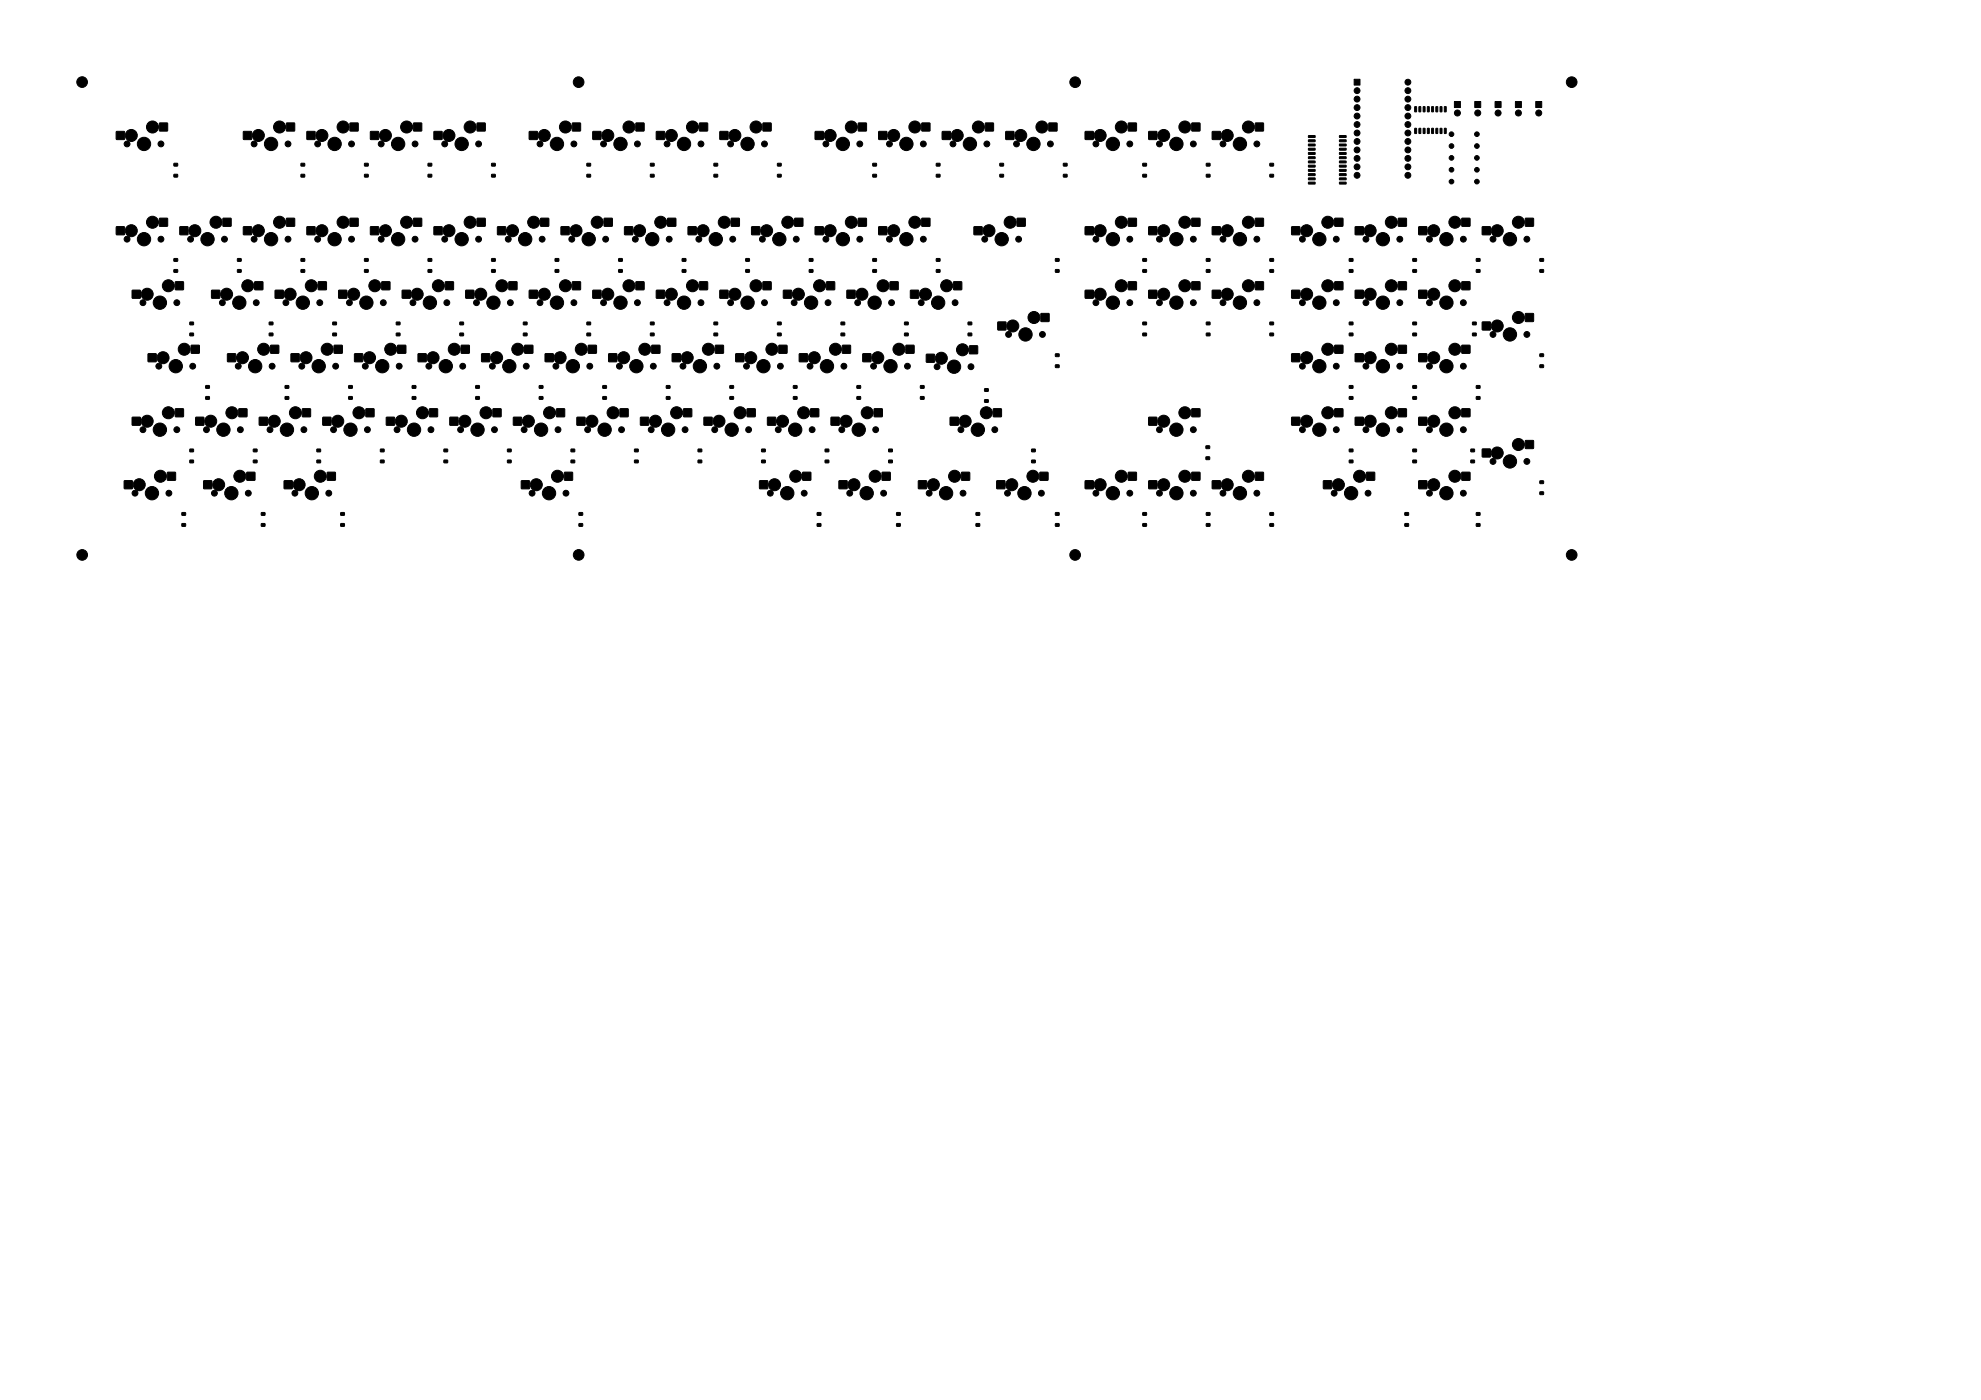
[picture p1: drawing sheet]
<svg xmlns="http://www.w3.org/2000/svg" width="594mm" height="420mm" viewBox="0 0 594 420" stroke-linecap="round" stroke-linejoin="round" font-family="sans-serif">
<g fill="#000" stroke="#000" stroke-width=".3">
<path d="M34.9 39.5h2.4v2.3h-2.4zM47.8 36.9h2.4v2.4h-2.4zM73 39.5h2.4v2.3h-2.4zM85.9 36.9h2.4v2.4h-2.4zM92 39.5h2.4v2.3h-2.4zM105 36.9h2.4v2.4h-2.4zM111.1 39.5h2.4v2.3h-2.4zM124 36.9h2.4v2.4h-2.4zM130.1 39.5h2.4v2.3h-2.4zM143.1 36.9h2.4v2.4h-2.4zM158.7 39.5h2.4v2.3h-2.4zM171.6 36.9h2.4v2.4h-2.4z"/>
<path d="M177.8 39.5h2.4v2.3h-2.4zM190.7 36.9h2.4v2.4h-2.4zM196.8 39.5h2.4v2.3h-2.4zM209.7 36.9h2.4v2.4h-2.4zM215.9 39.5h2.4v2.3h-2.4zM228.8 36.9h2.4v2.4h-2.4zM244.4 39.5h2.4v2.3h-2.4zM257.4 36.9h2.4v2.4h-2.4zM263.5 39.5h2.4v2.3h-2.4zM276.4 36.9h2.4v2.4h-2.4zM282.5 39.5h2.4v2.3h-2.4zM295.5 36.9h2.4v2.4h-2.4z"/>
<path d="M301.6 39.5h2.4v2.3h-2.4zM314.5 36.9h2.4v2.4h-2.4zM325.4 39.5h2.4v2.3h-2.4zM338.3 36.9h2.4v2.4h-2.4zM344.5 39.5h2.4v2.3h-2.4zM357.4 36.9h2.4v2.4h-2.4zM363.5 39.5h2.4v2.3h-2.4zM376.4 36.9h2.4v2.4h-2.4zM406 23.8h1.8v1.7h-1.8zM424.2 32l.6 .1-.1 1.5-.5-.1zM424.2 38.5l.6 .1-.1 1.5-.5-.1zM425.5 32l.5 .1v1.5l-.5-.1z"/>
<path d="M425.5 38.5l.5 .1v1.5l-.5-.1zM426.8 32l.5 .1-.1 1.5-.5-.1zM426.8 38.5l.5 .1-.1 1.5-.5-.1zM428 32l.6 .1-.1 1.5-.5-.1zM428 38.5l.6 .1-.1 1.5-.5-.1zM429.3 32l.5 .1v1.5l-.5-.1zM429.3 38.5l.5 .1v1.5l-.5-.1zM430.6 32l.5 .1-.1 1.5-.5-.1zM430.6 38.5l.5 .1-.1 1.5-.5-.1zM431.8 32l.6 .1-.1 1.5-.5-.1zM431.8 38.5l.6 .1-.1 1.5-.5-.1zM433.1 32l.6 .1-.1 1.5-.5-.1z"/>
<path d="M433.1 38.5l.6 .1-.1 1.5-.5-.1zM436.1 30.5h1.8v1.8h-1.8zM442.2 30.5h1.8v1.8h-1.8zM448.3 30.5h1.8v1.8h-1.8zM454.4 30.5h1.8v1.8h-1.8zM460.5 30.5h1.8v1.8h-1.8zM52.2 52.3h1v.8h-1zM52.2 49h1v.8h-1zM90.3 52.3h1v.8h-1zM90.3 49h1v.8h-1zM109.3 52.3h1.1v.8h-1.1zM109.3 49h1.1v.8h-1.1z"/>
<path d="M128.4 52.3h1v.8h-1zM128.4 49h1v.8h-1zM147.4 52.3h1.1v.8h-1.1zM147.4 49h1.1v.8h-1.1zM176 52.3h1.1v.8h-1.1zM176 49h1.1v.8h-1.1zM195 52.3h1.1v.8h-1.1zM195 49h1.1v.8h-1.1zM214.1 52.3h1.1v.8h-1.1zM214.1 49h1.1v.8h-1.1zM233.1 52.3h1.1v.8h-1.1zM233.1 49h1.1v.8h-1.1z"/>
<path d="M261.7 52.3h1.1v.8h-1.1zM261.7 49h1.1v.8h-1.1zM280.8 52.3h1v.8h-1zM280.8 49h1v.8h-1zM299.8 52.3h1.1v.8h-1.1zM299.8 49h1.1v.8h-1.1zM318.9 52.3h1v.8h-1zM318.9 49h1v.8h-1zM342.7 52.3h1.1v.8h-1.1zM342.7 49h1.1v.8h-1.1zM361.7 52.3h1.1v.8h-1.1zM361.7 49h1.1v.8h-1.1z"/>
<path d="M380.8 52.3h1.1v.8h-1.1zM380.8 49h1.1v.8h-1.1zM392.4 54.7l1.9-.1 .1 .5-2 .1zM392.4 53.4h1.9l.1 .5h-2zM392.4 52.1h1.9l.1 .5-2 .1zM392.4 50.9l1.9-.1 .1 .5-2 .1zM392.4 49.6h1.9l.1 .5h-2zM392.4 48.3h1.9l.1 .5-2 .1zM392.4 47.1l1.9-.1 .1 .5-2 .1zM392.4 45.8l1.9-.1 .1 .5-2 .1zM392.4 44.5h1.9l.1 .5-2 .1zM392.4 43.2h1.9l.1 .5-2 .1z"/>
<path d="M392.4 42l1.9-.1 .1 .5-2 .1zM392.4 40.7h1.9l.1 .5h-2zM401.7 40.7h1.9v.5h-1.9zM401.7 42l1.9-.1v.5l-1.9 .1zM401.7 43.2h1.9v.5l-1.9 .1zM401.7 44.5h1.9v.5l-1.9 .1zM401.7 45.8l1.9-.1v.5l-1.9 .1zM401.7 47.1l1.9-.1v.5l-1.9 .1zM401.7 48.3h1.9v.5l-1.9 .1zM401.7 49.6h1.9v.5h-1.9zM401.7 50.9l1.9-.1v.5l-1.9 .1zM401.7 52.1h1.9v.5l-1.9 .1z"/>
<path d="M401.7 53.4h1.9v.5h-1.9zM401.7 54.7l1.9-.1v.5l-1.9 .1zM34.9 68h2.4v2.4h-2.4zM47.8 65.5h2.4v2.4h-2.4zM52.2 77.6h1v.8h-1zM53.9 68h2.4v2.4h-2.4zM66.9 65.5h2.4v2.4h-2.4zM71.2 77.6h1.1v.8h-1.1zM73 68h2.4v2.4h-2.4zM85.9 65.5h2.4v2.4h-2.4zM90.3 77.6h1v.8h-1zM92 68h2.4v2.4h-2.4z"/>
<path d="M105 65.5h2.4v2.4h-2.4zM109.3 77.6h1.1v.8h-1.1zM111.1 68h2.4v2.4h-2.4zM124 65.5h2.4v2.4h-2.4zM128.4 77.6h1v.8h-1zM130.1 68h2.4v2.4h-2.4zM143.1 65.5h2.4v2.4h-2.4zM147.4 77.6h1.1v.8h-1.1zM149.2 68h2.4v2.4h-2.4zM162.1 65.5h2.4v2.4h-2.4zM166.5 77.6h1v.8h-1zM168.2 68h2.4v2.4h-2.4z"/>
<path d="M181.2 65.5h2.4v2.4h-2.4zM185.5 77.6h1.1v.8h-1.1zM187.3 68h2.4v2.4h-2.4zM200.2 65.5h2.4v2.4h-2.4zM204.6 77.6h1v.8h-1zM206.3 68h2.4v2.4h-2.4zM219.3 65.5h2.4v2.4h-2.4zM223.6 77.6h1.1v.8h-1.1zM225.4 68h2.4v2.4h-2.4zM238.3 65.5h2.4v2.4h-2.4zM242.7 77.6h1v.8h-1zM244.4 68h2.4v2.4h-2.4z"/>
<path d="M257.4 65.5h2.4v2.4h-2.4zM261.7 77.6h1.1v.8h-1.1zM263.5 68h2.4v2.4h-2.4zM276.4 65.5h2.4v2.4h-2.4zM280.8 77.6h1v.8h-1zM292.1 68h2.4v2.4h-2.4zM305 65.5h2.4v2.4h-2.4zM316.5 77.6h1.1v.8h-1.1zM325.4 68h2.4v2.4h-2.4zM338.3 65.5h2.4v2.4h-2.4zM342.7 77.6h1.1v.8h-1.1zM344.5 68h2.4v2.4h-2.4z"/>
<path d="M357.4 65.5h2.4v2.4h-2.4zM361.7 77.6h1.1v.8h-1.1zM363.5 68h2.4v2.4h-2.4zM376.4 65.5h2.4v2.4h-2.4zM380.8 77.6h1.1v.8h-1.1zM387.3 68h2.4v2.4h-2.4zM400.2 65.5h2.4v2.4h-2.4zM404.6 77.6h1.1v.8h-1.1zM406.4 68h2.4v2.4h-2.4zM419.3 65.5h2.4v2.4h-2.4zM423.6 77.6h1.1v.8h-1.1zM425.4 68h2.4v2.4h-2.4z"/>
<path d="M438.3 65.5h2.4v2.4h-2.4zM442.7 77.6h1.1v.8h-1.1zM444.5 68h2.4v2.4h-2.4zM457.4 65.5h2.4v2.4h-2.4zM461.7 77.6h1.1v.8h-1.1zM39.7 87.1h2.4v2.3h-2.4zM52.2 80.9h1v.8h-1zM52.6 84.5h2.4v2.4h-2.4zM56.9 96.6h1.1v.8h-1.1zM63.5 87.1h2.4v2.3h-2.4zM71.2 80.9h1.1v.8h-1.1zM76.4 84.5h2.4v2.4h-2.4z"/>
<path d="M80.7 96.6h1.1v.8h-1.1zM82.5 87.1h2.4v2.3h-2.4zM90.3 80.9h1v.8h-1zM95.4 84.5h2.4v2.4h-2.4zM99.8 96.6h1.1v.8h-1.1zM101.6 87.1h2.4v2.3h-2.4zM109.3 80.9h1.1v.8h-1.1zM114.5 84.5h2.4v2.4h-2.4zM118.8 96.6h1.1v.8h-1.1zM120.6 87.1h2.4v2.3h-2.4zM128.4 80.9h1v.8h-1zM133.5 84.5h2.4v2.4h-2.4z"/>
<path d="M137.9 96.6h1.1v.8h-1.1zM139.7 87.1h2.4v2.3h-2.4zM147.4 80.9h1.1v.8h-1.1zM152.6 84.5h2.4v2.4h-2.4zM156.9 96.6h1.1v.8h-1.1zM158.7 87.1h2.4v2.3h-2.4zM166.5 80.9h1v.8h-1zM171.6 84.5h2.4v2.4h-2.4zM176 96.6h1.1v.8h-1.1zM177.8 87.1h2.4v2.3h-2.4zM185.5 80.9h1.1v.8h-1.1zM190.7 84.5h2.4v2.4h-2.4z"/>
<path d="M195 96.6h1.1v.8h-1.1zM196.8 87.1h2.4v2.3h-2.4zM204.6 80.9h1v.8h-1zM209.7 84.5h2.4v2.4h-2.4zM214.1 96.6h1.1v.8h-1.1zM215.9 87.1h2.4v2.3h-2.4zM223.6 80.9h1.1v.8h-1.1zM228.8 84.5h2.4v2.4h-2.4zM233.1 96.6h1.1v.8h-1.1zM234.9 87.1h2.4v2.3h-2.4zM242.7 80.9h1v.8h-1zM247.8 84.5h2.4v2.4h-2.4z"/>
<path d="M252.2 96.6h1.1v.8h-1.1zM254 87.1h2.4v2.3h-2.4zM261.7 80.9h1.1v.8h-1.1zM266.9 84.5h2.4v2.4h-2.4zM271.2 96.6h1.1v.8h-1.1zM273 87.1h2.4v2.3h-2.4zM280.8 80.9h1v.8h-1zM285.9 84.5h2.4v2.4h-2.4zM290.3 96.6h1.1v.8h-1.1zM299.2 96.6h2.4v2.4h-2.4zM312.1 94.1h2.4v2.3h-2.4zM316.5 80.9h1.1v.8h-1.1z"/>
<path d="M325.4 87.1h2.4v2.3h-2.4zM338.3 84.5h2.4v2.4h-2.4zM342.7 80.9h1.1v.8h-1.1zM342.7 96.6h1.1v.8h-1.1zM344.5 87.1h2.4v2.3h-2.4zM357.4 84.5h2.4v2.4h-2.4zM361.7 80.9h1.1v.8h-1.1zM361.7 96.6h1.1v.8h-1.1zM363.5 87.1h2.4v2.3h-2.4zM376.4 84.5h2.4v2.4h-2.4zM380.8 80.9h1.1v.8h-1.1zM380.8 96.6h1.1v.8h-1.1z"/>
<path d="M387.3 87.1h2.4v2.3h-2.4zM400.2 84.5h2.4v2.4h-2.4zM404.6 96.6h1.1v.8h-1.1zM404.6 80.9h1.1v.8h-1.1zM406.4 87.1h2.4v2.3h-2.4zM419.3 84.5h2.4v2.4h-2.4zM423.6 80.9h1.1v.8h-1.1zM423.6 96.6h1.1v.8h-1.1zM425.4 87.1h2.4v2.3h-2.4zM438.3 84.5h2.4v2.4h-2.4zM441.6 96.6h1v.8h-1zM442.7 80.9h1.1v.8h-1.1z"/>
<path d="M444.5 96.6h2.4v2.4h-2.4zM457.4 94.1h2.4v2.3h-2.4zM461.7 80.9h1.1v.8h-1.1zM44.4 106.1h2.4v2.4h-2.4zM56.9 99.9h1.1v.8h-1.1zM57.3 103.6h2.4v2.4h-2.4zM61.7 119h1.1v.8h-1.1zM61.7 115.7h1.1v.8h-1.1zM68.2 106.1h2.4v2.4h-2.4zM80.7 99.9h1.1v.8h-1.1zM81.2 103.6h2.4v2.4h-2.4zM85.5 119h1.1v.8h-1.1z"/>
<path d="M85.5 115.7h1.1v.8h-1.1zM87.3 106.1h2.4v2.4h-2.4zM99.8 99.9h1.1v.8h-1.1zM100.2 103.6h2.4v2.4h-2.4zM104.6 119h1v.8h-1zM104.6 115.7h1v.8h-1zM106.3 106.1h2.4v2.4h-2.4zM118.8 99.9h1.1v.8h-1.1zM119.3 103.6h2.4v2.4h-2.4zM123.6 119h1.1v.8h-1.1zM123.6 115.7h1.1v.8h-1.1zM125.4 106.1h2.4v2.4h-2.4z"/>
<path d="M137.9 99.9h1.1v.8h-1.1zM138.3 103.6h2.4v2.4h-2.4zM142.7 119h1v.8h-1zM142.7 115.7h1v.8h-1zM144.4 106.1h2.4v2.4h-2.4zM156.9 99.9h1.1v.8h-1.1zM157.4 103.6h2.4v2.4h-2.4zM161.7 119h1.1v.8h-1.1zM161.7 115.7h1.1v.8h-1.1zM163.5 106.1h2.4v2.4h-2.4zM176 99.9h1.1v.8h-1.1zM176.4 103.6h2.4v2.4h-2.4z"/>
<path d="M180.8 119h1v.8h-1zM180.8 115.7h1v.8h-1zM182.5 106.1h2.4v2.4h-2.4zM195 99.9h1.1v.8h-1.1zM195.5 103.6h2.4v2.4h-2.4zM199.8 119h1.1v.8h-1.1zM199.8 115.7h1.1v.8h-1.1zM201.6 106.1h2.4v2.4h-2.4zM214.1 99.9h1.1v.8h-1.1zM214.5 103.6h2.4v2.4h-2.4zM218.9 119h1v.8h-1zM218.9 115.7h1v.8h-1z"/>
<path d="M220.6 106.1h2.4v2.4h-2.4zM233.1 99.9h1.1v.8h-1.1zM233.6 103.6h2.4v2.4h-2.4zM237.9 119h1.1v.8h-1.1zM237.9 115.7h1.1v.8h-1.1zM239.7 106.1h2.4v2.4h-2.4zM252.2 99.9h1.1v.8h-1.1zM252.6 103.6h2.4v2.4h-2.4zM257 119h1v.8h-1zM257 115.7h1v.8h-1zM258.7 106.1h2.4v2.4h-2.4zM271.2 99.9h1.1v.8h-1.1z"/>
<path d="M271.7 103.6h2.4v2.4h-2.4zM276 119h1.1v.8h-1.1zM276 115.7h1.1v.8h-1.1zM277.8 106.3h2.4v2.4h-2.4zM290.3 99.9h1.1v.8h-1.1zM290.7 103.8h2.4v2.3h-2.4zM295.2 116.6h1.1v.8h-1.1zM316.5 109.5h1.1v.7h-1.1zM316.5 106.2h1.1v.7h-1.1zM342.7 99.9h1.1v.8h-1.1zM361.7 99.9h1.1v.8h-1.1zM380.8 99.9h1.1v.8h-1.1z"/>
<path d="M387.3 106.1h2.4v2.4h-2.4zM400.2 103.6h2.4v2.4h-2.4zM404.6 99.9h1.1v.8h-1.1zM404.6 119h1.1v.8h-1.1zM404.6 115.7h1.1v.8h-1.1zM406.4 106.1h2.4v2.4h-2.4zM419.3 103.6h2.4v2.4h-2.4zM423.6 119h1.1v.8h-1.1zM423.6 115.7h1.1v.8h-1.1zM423.6 99.9h1.1v.8h-1.1zM425.4 106.1h2.4v2.4h-2.4zM438.3 103.6h2.4v2.4h-2.4z"/>
<path d="M441.6 99.9h1v.8h-1zM442.7 119h1.1v.8h-1.1zM442.7 115.7h1.1v.8h-1.1zM461.7 109.5h1.1v.7h-1.1zM461.7 106.2h1.1v.7h-1.1zM39.7 125.2h2.4v2.3h-2.4zM52.6 122.6h2.4v2.4h-2.4zM56.9 138h1.1v.8h-1.1zM56.9 134.7h1.1v.8h-1.1zM58.7 125.2h2.4v2.3h-2.4zM71.6 122.6h2.4v2.4h-2.4zM76 138h1.1v.8h-1.1z"/>
<path d="M76 134.7h1.1v.8h-1.1zM77.8 125.2h2.4v2.3h-2.4zM90.7 122.6h2.4v2.4h-2.4zM95 138h1.1v.8h-1.1zM95 134.7h1.1v.8h-1.1zM96.8 125.2h2.4v2.3h-2.4zM109.7 122.6h2.4v2.4h-2.4zM114.1 138h1.1v.8h-1.1zM114.1 134.7h1.1v.8h-1.1zM115.9 125.2h2.4v2.3h-2.4zM128.8 122.6h2.4v2.4h-2.4zM133.1 138h1.1v.8h-1.1z"/>
<path d="M133.1 134.7h1.1v.8h-1.1zM134.9 125.2h2.4v2.3h-2.4zM147.8 122.6h2.4v2.4h-2.4zM152.2 138h1.1v.8h-1.1zM152.2 134.7h1.1v.8h-1.1zM154 125.2h2.4v2.3h-2.4zM166.9 122.6h2.4v2.4h-2.4zM171.2 138h1.1v.8h-1.1zM171.2 134.7h1.1v.8h-1.1zM173 125.2h2.4v2.3h-2.4zM185.9 122.6h2.4v2.4h-2.4zM190.3 138h1.1v.8h-1.1z"/>
<path d="M190.3 134.7h1.1v.8h-1.1zM192.1 125.2h2.4v2.3h-2.4zM205 122.6h2.4v2.4h-2.4zM209.3 138h1.1v.8h-1.1zM209.3 134.7h1.1v.8h-1.1zM211.1 125.2h2.4v2.3h-2.4zM224 122.6h2.4v2.4h-2.4zM228.4 138h1.1v.8h-1.1zM228.4 134.7h1.1v.8h-1.1zM230.2 125.2h2.4v2.3h-2.4zM243.1 122.6h2.4v2.4h-2.4zM247.4 138h1.1v.8h-1.1z"/>
<path d="M247.4 134.7h1.1v.8h-1.1zM249.2 125.2h2.4v2.3h-2.4zM262.1 122.6h2.4v2.4h-2.4zM266.5 138h1.1v.8h-1.1zM266.5 134.7h1.1v.8h-1.1zM284.9 125.2h2.4v2.3h-2.4zM295.2 119.9h1.1v.8h-1.1zM297.9 122.6h2.4v2.4h-2.4zM309.3 138h1.1v.8h-1.1zM309.3 134.7h1.1v.8h-1.1zM344.5 125.2h2.4v2.3h-2.4zM357.4 122.6h2.4v2.4h-2.4z"/>
<path d="M361.6 137.1l1-.1 .1 .8-1 .1zM361.6 133.8h1.1v.7h-1.1zM387.3 125.2h2.4v2.3h-2.4zM400.2 122.6h2.4v2.4h-2.4zM404.6 138h1.1v.8h-1.1zM404.6 134.7h1.1v.8h-1.1zM406.4 125.2h2.4v2.3h-2.4zM419.3 122.6h2.4v2.4h-2.4zM423.6 138h1.1v.8h-1.1zM423.6 134.7h1.1v.8h-1.1zM425.4 125.2h2.4v2.3h-2.4zM438.3 122.6h2.4v2.4h-2.4z"/>
<path d="M441 138h1.1v.8h-1.1zM441 134.7h1.1v.8h-1.1zM444.5 134.7h2.4v2.4h-2.4zM457.4 132.2h2.4v2.3h-2.4zM37.3 144.2h2.4v2.4h-2.4zM50.2 141.7h2.4v2.4h-2.4zM54.6 157.1h1v.8h-1zM54.6 153.8h1v.8h-1zM61.1 144.2h2.4v2.4h-2.4zM74 141.7h2.4v2.4h-2.4zM78.4 157.1h1v.8h-1zM78.4 153.8h1v.8h-1z"/>
<path d="M85.2 144.2h2.4v2.4h-2.4zM98.1 141.7h2.4v2.4h-2.4zM102.2 157.1h1v.8h-1zM102.2 153.8h1v.8h-1zM156.3 144.2h2.4v2.4h-2.4zM169.3 141.7h2.4v2.4h-2.4zM173.6 157.1h1.1v.8h-1.1zM173.6 153.8h1.1v.8h-1.1zM227.8 144.2h2.4v2.4h-2.4zM240.7 141.7h2.4v2.4h-2.4zM245.1 157.1h1v.8h-1zM245.1 153.8h1v.8h-1z"/>
<path d="M251.6 144.2h2.4v2.4h-2.4zM264.5 141.7h2.4v2.4h-2.4zM268.9 157.1h1v.8h-1zM268.9 153.8h1v.8h-1zM275.4 144.2h2.4v2.4h-2.4zM288.3 141.7h2.4v2.4h-2.4zM292.7 157.1h1v.8h-1zM292.7 153.8h1v.8h-1zM298.9 144.2h2.4v2.4h-2.4zM311.8 141.7h2.4v2.4h-2.4zM316.5 157.1h1.1v.8h-1.1zM316.5 153.8h1.1v.8h-1.1z"/>
<path d="M325.4 144.2h2.4v2.4h-2.4zM338.3 141.7h2.4v2.4h-2.4zM342.7 157.1h1.1v.8h-1.1zM342.7 153.8h1.1v.8h-1.1zM344.5 144.2h2.4v2.4h-2.4zM357.4 141.7h2.4v2.4h-2.4zM361.7 157.1h1.1v.8h-1.1zM361.7 153.8h1.1v.8h-1.1zM363.5 144.2h2.4v2.4h-2.4zM376.4 141.7h2.4v2.4h-2.4zM380.8 157.1h1.1v.8h-1.1zM380.8 153.8h1.1v.8h-1.1z"/>
<path d="M396.8 144.2h2.4v2.4h-2.4zM409.8 141.7h2.4v2.4h-2.4zM421.3 157.1h1v.8h-1zM421.3 153.8h1v.8h-1zM425.4 144.2h2.4v2.4h-2.4zM438.3 141.7h2.4v2.4h-2.4zM442.7 157.1h1.1v.8h-1.1zM442.7 153.8h1.1v.8h-1.1zM461.7 147.6h1.1v.7h-1.1zM461.7 144.3h1.1v.7h-1.1z"/>
<circle cx="24.6" cy="24.6" r="1.6"/>
<circle cx="45.7" cy="38.1" r="1.8"/>
<circle cx="83.8" cy="38.1" r="1.8"/>
<circle cx="102.9" cy="38.1" r="1.8"/>
<circle cx="121.9" cy="38.1" r="1.8"/>
<circle cx="141" cy="38.1" r="1.8"/>
<circle cx="169.5" cy="38.1" r="1.8"/>
<circle cx="173.5" cy="24.6" r="1.6"/>
<circle cx="188.6" cy="38.1" r="1.8"/>
<circle cx="207.6" cy="38.1" r="1.8"/>
<circle cx="226.7" cy="38.1" r="1.8"/>
<circle cx="255.3" cy="38.1" r="1.8"/>
<circle cx="274.3" cy="38.1" r="1.8"/>
<circle cx="293.4" cy="38.1" r="1.8"/>
<circle cx="312.4" cy="38.1" r="1.8"/>
<circle cx="322.4" cy="24.7" r="1.6"/>
<circle cx="336.2" cy="38.1" r="1.8"/>
<circle cx="355.3" cy="38.1" r="1.8"/>
<circle cx="374.3" cy="38.1" r="1.8"/>
<circle cx="406.9" cy="39.9" r=".88"/>
<circle cx="406.9" cy="34.8" r=".88"/>
<circle cx="406.9" cy="27.2" r=".88"/>
<circle cx="406.9" cy="29.7" r=".88"/>
<circle cx="406.9" cy="32.3" r=".88"/>
<circle cx="406.9" cy="37.4" r=".88"/>
<circle cx="422.2" cy="32.3" r=".88"/>
<circle cx="422.2" cy="27.2" r=".88"/>
<circle cx="422.2" cy="39.9" r=".88"/>
<circle cx="422.2" cy="37.4" r=".88"/>
<circle cx="422.2" cy="24.7" r=".88"/>
<circle cx="422.2" cy="34.8" r=".88"/>
<circle cx="422.2" cy="29.7" r=".88"/>
<circle cx="437" cy="33.9" r=".9"/>
<circle cx="443.1" cy="33.9" r=".9"/>
<circle cx="449.2" cy="33.9" r=".9"/>
<circle cx="455.3" cy="33.9" r=".9"/>
<circle cx="461.4" cy="33.9" r=".9"/>
<circle cx="471.3" cy="24.6" r="1.6"/>
<circle cx="38.1" cy="43.2" r=".87"/>
<circle cx="39.4" cy="40.6" r="1.8"/>
<circle cx="43.2" cy="43.2" r="2"/>
<circle cx="48.3" cy="43.2" r=".87"/>
<circle cx="76.2" cy="43.2" r=".87"/>
<circle cx="77.5" cy="40.6" r="1.8"/>
<circle cx="81.3" cy="43.2" r="2"/>
<circle cx="86.4" cy="43.2" r=".87"/>
<circle cx="95.2" cy="43.2" r=".87"/>
<circle cx="96.5" cy="40.6" r="1.8"/>
<circle cx="100.3" cy="43.2" r="2"/>
<circle cx="105.4" cy="43.2" r=".87"/>
<circle cx="114.3" cy="43.2" r=".87"/>
<circle cx="115.6" cy="40.6" r="1.8"/>
<circle cx="119.4" cy="43.2" r="2"/>
<circle cx="124.5" cy="43.2" r=".87"/>
<circle cx="133.3" cy="43.2" r=".87"/>
<circle cx="134.6" cy="40.6" r="1.8"/>
<circle cx="138.4" cy="43.2" r="2"/>
<circle cx="143.5" cy="43.2" r=".87"/>
<circle cx="161.9" cy="43.2" r=".87"/>
<circle cx="163.2" cy="40.6" r="1.8"/>
<circle cx="167" cy="43.2" r="2"/>
<circle cx="172.1" cy="43.2" r=".87"/>
<circle cx="181" cy="43.2" r=".87"/>
<circle cx="182.2" cy="40.6" r="1.8"/>
<circle cx="186.1" cy="43.2" r="2"/>
<circle cx="191.1" cy="43.2" r=".87"/>
<circle cx="200" cy="43.2" r=".87"/>
<circle cx="201.3" cy="40.6" r="1.8"/>
<circle cx="205.1" cy="43.2" r="2"/>
<circle cx="210.2" cy="43.2" r=".87"/>
<circle cx="219.1" cy="43.2" r=".87"/>
<circle cx="220.3" cy="40.6" r="1.8"/>
<circle cx="224.2" cy="43.2" r="2"/>
<circle cx="229.2" cy="43.2" r=".87"/>
<circle cx="247.6" cy="43.2" r=".87"/>
<circle cx="248.9" cy="40.6" r="1.8"/>
<circle cx="252.7" cy="43.2" r="2"/>
<circle cx="257.8" cy="43.2" r=".87"/>
<circle cx="266.7" cy="43.2" r=".87"/>
<circle cx="268" cy="40.6" r="1.8"/>
<circle cx="271.8" cy="43.2" r="2"/>
<circle cx="276.9" cy="43.2" r=".87"/>
<circle cx="285.8" cy="43.2" r=".87"/>
<circle cx="287" cy="40.6" r="1.8"/>
<circle cx="290.8" cy="43.2" r="2"/>
<circle cx="295.9" cy="43.2" r=".87"/>
<circle cx="304.8" cy="43.2" r=".87"/>
<circle cx="306.1" cy="40.6" r="1.8"/>
<circle cx="309.9" cy="43.2" r="2"/>
<circle cx="315" cy="43.2" r=".87"/>
<circle cx="328.6" cy="43.2" r=".87"/>
<circle cx="329.9" cy="40.6" r="1.8"/>
<circle cx="333.7" cy="43.2" r="2"/>
<circle cx="338.8" cy="43.2" r=".87"/>
<circle cx="347.7" cy="43.2" r=".87"/>
<circle cx="348.9" cy="40.6" r="1.8"/>
<circle cx="352.7" cy="43.2" r="2"/>
<circle cx="357.8" cy="43.2" r=".87"/>
<circle cx="366.7" cy="43.2" r=".87"/>
<circle cx="368" cy="40.6" r="1.8"/>
<circle cx="371.8" cy="43.2" r="2"/>
<circle cx="376.9" cy="43.2" r=".87"/>
<circle cx="406.9" cy="45" r=".88"/>
<circle cx="406.9" cy="50.1" r=".88"/>
<circle cx="406.9" cy="47.5" r=".88"/>
<circle cx="406.9" cy="52.6" r=".88"/>
<circle cx="406.9" cy="42.4" r=".88"/>
<circle cx="422.2" cy="42.4" r=".88"/>
<circle cx="422.2" cy="52.6" r=".88"/>
<circle cx="422.2" cy="47.5" r=".88"/>
<circle cx="422.2" cy="50.1" r=".88"/>
<circle cx="422.2" cy="45" r=".88"/>
<circle cx="435.2" cy="43.8" r=".7"/>
<circle cx="435.2" cy="54.5" r=".7"/>
<circle cx="435.2" cy="40.3" r=".7"/>
<circle cx="435.2" cy="50.9" r=".7"/>
<circle cx="435.2" cy="47.4" r=".7"/>
<circle cx="442.8" cy="50.9" r=".7"/>
<circle cx="442.8" cy="54.5" r=".7"/>
<circle cx="442.8" cy="40.3" r=".7"/>
<circle cx="442.8" cy="47.4" r=".7"/>
<circle cx="442.8" cy="43.8" r=".7"/>
<circle cx="38.1" cy="71.8" r=".87"/>
<circle cx="39.4" cy="69.2" r="1.8"/>
<circle cx="43.2" cy="71.8" r="2"/>
<circle cx="45.7" cy="66.7" r="1.8"/>
<circle cx="48.3" cy="71.8" r=".87"/>
<circle cx="57.1" cy="71.8" r=".87"/>
<circle cx="58.4" cy="69.2" r="1.8"/>
<circle cx="62.2" cy="71.8" r="2"/>
<circle cx="64.8" cy="66.7" r="1.8"/>
<circle cx="67.3" cy="71.8" r=".87"/>
<circle cx="76.2" cy="71.8" r=".87"/>
<circle cx="77.5" cy="69.2" r="1.8"/>
<circle cx="81.3" cy="71.8" r="2"/>
<circle cx="83.8" cy="66.7" r="1.8"/>
<circle cx="86.4" cy="71.8" r=".87"/>
<circle cx="95.2" cy="71.8" r=".87"/>
<circle cx="96.5" cy="69.2" r="1.8"/>
<circle cx="100.3" cy="71.8" r="2"/>
<circle cx="102.9" cy="66.7" r="1.8"/>
<circle cx="105.4" cy="71.8" r=".87"/>
<circle cx="114.3" cy="71.8" r=".87"/>
<circle cx="115.6" cy="69.2" r="1.8"/>
<circle cx="119.4" cy="71.8" r="2"/>
<circle cx="121.9" cy="66.7" r="1.8"/>
<circle cx="124.5" cy="71.8" r=".87"/>
<circle cx="133.3" cy="71.8" r=".87"/>
<circle cx="134.6" cy="69.2" r="1.8"/>
<circle cx="138.4" cy="71.8" r="2"/>
<circle cx="141" cy="66.7" r="1.8"/>
<circle cx="143.5" cy="71.8" r=".87"/>
<circle cx="152.4" cy="71.8" r=".87"/>
<circle cx="153.7" cy="69.2" r="1.8"/>
<circle cx="157.5" cy="71.8" r="2"/>
<circle cx="160" cy="66.7" r="1.8"/>
<circle cx="162.6" cy="71.8" r=".87"/>
<circle cx="171.4" cy="71.8" r=".87"/>
<circle cx="172.7" cy="69.2" r="1.8"/>
<circle cx="176.5" cy="71.8" r="2"/>
<circle cx="179.1" cy="66.7" r="1.8"/>
<circle cx="181.6" cy="71.8" r=".87"/>
<circle cx="190.5" cy="71.8" r=".87"/>
<circle cx="191.8" cy="69.2" r="1.8"/>
<circle cx="195.6" cy="71.8" r="2"/>
<circle cx="198.1" cy="66.7" r="1.8"/>
<circle cx="200.7" cy="71.8" r=".87"/>
<circle cx="209.5" cy="71.8" r=".87"/>
<circle cx="210.8" cy="69.2" r="1.8"/>
<circle cx="214.6" cy="71.8" r="2"/>
<circle cx="217.2" cy="66.7" r="1.8"/>
<circle cx="219.7" cy="71.8" r=".87"/>
<circle cx="228.6" cy="71.8" r=".87"/>
<circle cx="229.9" cy="69.2" r="1.8"/>
<circle cx="233.7" cy="71.8" r="2"/>
<circle cx="236.2" cy="66.7" r="1.8"/>
<circle cx="238.8" cy="71.8" r=".87"/>
<circle cx="247.6" cy="71.8" r=".87"/>
<circle cx="248.9" cy="69.2" r="1.8"/>
<circle cx="252.7" cy="71.8" r="2"/>
<circle cx="255.3" cy="66.7" r="1.8"/>
<circle cx="257.8" cy="71.8" r=".87"/>
<circle cx="266.7" cy="71.8" r=".87"/>
<circle cx="268" cy="69.2" r="1.8"/>
<circle cx="271.8" cy="71.8" r="2"/>
<circle cx="274.3" cy="66.7" r="1.8"/>
<circle cx="276.9" cy="71.8" r=".87"/>
<circle cx="295.3" cy="71.8" r=".87"/>
<circle cx="296.5" cy="69.2" r="1.8"/>
<circle cx="300.4" cy="71.8" r="2"/>
<circle cx="302.9" cy="66.7" r="1.8"/>
<circle cx="305.4" cy="71.8" r=".87"/>
<circle cx="328.6" cy="71.8" r=".87"/>
<circle cx="329.9" cy="69.2" r="1.8"/>
<circle cx="333.7" cy="71.8" r="2"/>
<circle cx="336.2" cy="66.7" r="1.8"/>
<circle cx="338.8" cy="71.8" r=".87"/>
<circle cx="347.7" cy="71.8" r=".87"/>
<circle cx="348.9" cy="69.2" r="1.8"/>
<circle cx="352.7" cy="71.8" r="2"/>
<circle cx="355.3" cy="66.7" r="1.8"/>
<circle cx="357.8" cy="71.8" r=".87"/>
<circle cx="366.7" cy="71.8" r=".87"/>
<circle cx="368" cy="69.2" r="1.8"/>
<circle cx="371.8" cy="71.8" r="2"/>
<circle cx="374.3" cy="66.7" r="1.8"/>
<circle cx="376.9" cy="71.8" r=".87"/>
<circle cx="390.5" cy="71.8" r=".87"/>
<circle cx="391.8" cy="69.2" r="1.8"/>
<circle cx="395.6" cy="71.8" r="2"/>
<circle cx="398.1" cy="66.7" r="1.8"/>
<circle cx="400.7" cy="71.8" r=".87"/>
<circle cx="409.6" cy="71.8" r=".87"/>
<circle cx="410.8" cy="69.2" r="1.8"/>
<circle cx="414.7" cy="71.8" r="2"/>
<circle cx="417.2" cy="66.7" r="1.8"/>
<circle cx="419.7" cy="71.8" r=".87"/>
<circle cx="428.6" cy="71.8" r=".87"/>
<circle cx="429.9" cy="69.2" r="1.8"/>
<circle cx="433.7" cy="71.8" r="2"/>
<circle cx="436.2" cy="66.7" r="1.8"/>
<circle cx="438.8" cy="71.8" r=".87"/>
<circle cx="447.7" cy="71.8" r=".87"/>
<circle cx="448.9" cy="69.2" r="1.8"/>
<circle cx="452.8" cy="71.8" r="2"/>
<circle cx="455.3" cy="66.7" r="1.8"/>
<circle cx="457.8" cy="71.8" r=".87"/>
<circle cx="42.9" cy="90.8" r=".87"/>
<circle cx="44.1" cy="88.3" r="1.8"/>
<circle cx="47.9" cy="90.8" r="2"/>
<circle cx="50.5" cy="85.7" r="1.8"/>
<circle cx="53" cy="90.8" r=".87"/>
<circle cx="66.7" cy="90.8" r=".87"/>
<circle cx="67.9" cy="88.3" r="1.8"/>
<circle cx="71.8" cy="90.8" r="2"/>
<circle cx="74.3" cy="85.7" r="1.8"/>
<circle cx="76.8" cy="90.8" r=".87"/>
<circle cx="85.7" cy="90.8" r=".87"/>
<circle cx="87" cy="88.3" r="1.8"/>
<circle cx="90.8" cy="90.8" r="2"/>
<circle cx="93.3" cy="85.7" r="1.8"/>
<circle cx="95.9" cy="90.8" r=".87"/>
<circle cx="104.8" cy="90.8" r=".87"/>
<circle cx="106" cy="88.3" r="1.8"/>
<circle cx="109.9" cy="90.8" r="2"/>
<circle cx="112.4" cy="85.7" r="1.8"/>
<circle cx="114.9" cy="90.8" r=".87"/>
<circle cx="123.8" cy="90.8" r=".87"/>
<circle cx="125.1" cy="88.3" r="1.8"/>
<circle cx="128.9" cy="90.8" r="2"/>
<circle cx="131.4" cy="85.7" r="1.8"/>
<circle cx="134" cy="90.8" r=".87"/>
<circle cx="142.9" cy="90.8" r=".87"/>
<circle cx="144.1" cy="88.3" r="1.8"/>
<circle cx="148" cy="90.8" r="2"/>
<circle cx="150.5" cy="85.7" r="1.8"/>
<circle cx="153" cy="90.8" r=".87"/>
<circle cx="161.9" cy="90.8" r=".87"/>
<circle cx="163.2" cy="88.3" r="1.8"/>
<circle cx="167" cy="90.8" r="2"/>
<circle cx="169.5" cy="85.7" r="1.8"/>
<circle cx="172.1" cy="90.8" r=".87"/>
<circle cx="181" cy="90.8" r=".87"/>
<circle cx="182.2" cy="88.3" r="1.8"/>
<circle cx="186.1" cy="90.8" r="2"/>
<circle cx="188.6" cy="85.7" r="1.8"/>
<circle cx="191.1" cy="90.8" r=".87"/>
<circle cx="200" cy="90.8" r=".87"/>
<circle cx="201.3" cy="88.3" r="1.8"/>
<circle cx="205.1" cy="90.8" r="2"/>
<circle cx="207.6" cy="85.7" r="1.8"/>
<circle cx="210.2" cy="90.8" r=".87"/>
<circle cx="219.1" cy="90.8" r=".87"/>
<circle cx="220.3" cy="88.3" r="1.8"/>
<circle cx="224.2" cy="90.8" r="2"/>
<circle cx="226.7" cy="85.7" r="1.8"/>
<circle cx="229.2" cy="90.8" r=".87"/>
<circle cx="238.1" cy="90.8" r=".87"/>
<circle cx="239.4" cy="88.3" r="1.8"/>
<circle cx="243.2" cy="90.8" r="2"/>
<circle cx="245.7" cy="85.7" r="1.8"/>
<circle cx="248.3" cy="90.8" r=".87"/>
<circle cx="257.2" cy="90.8" r=".87"/>
<circle cx="258.4" cy="88.3" r="1.8"/>
<circle cx="262.3" cy="90.8" r="2"/>
<circle cx="264.8" cy="85.7" r="1.8"/>
<circle cx="267.3" cy="90.8" r=".87"/>
<circle cx="276.2" cy="90.8" r=".87"/>
<circle cx="277.5" cy="88.3" r="1.8"/>
<circle cx="281.3" cy="90.8" r="2"/>
<circle cx="283.8" cy="85.7" r="1.8"/>
<circle cx="286.4" cy="90.8" r=".87"/>
<circle cx="303.7" cy="97.8" r="1.8"/>
<circle cx="310" cy="95.3" r="1.8"/>
<circle cx="328.6" cy="90.8" r=".87"/>
<circle cx="329.9" cy="88.3" r="1.8"/>
<circle cx="333.7" cy="90.8" r="2"/>
<circle cx="336.2" cy="85.7" r="1.8"/>
<circle cx="338.8" cy="90.8" r=".87"/>
<circle cx="347.7" cy="90.8" r=".87"/>
<circle cx="348.9" cy="88.3" r="1.8"/>
<circle cx="352.7" cy="90.8" r="2"/>
<circle cx="355.3" cy="85.7" r="1.8"/>
<circle cx="357.8" cy="90.8" r=".87"/>
<circle cx="366.7" cy="90.8" r=".87"/>
<circle cx="368" cy="88.3" r="1.8"/>
<circle cx="371.8" cy="90.8" r="2"/>
<circle cx="374.3" cy="85.7" r="1.8"/>
<circle cx="376.9" cy="90.8" r=".87"/>
<circle cx="390.5" cy="90.8" r=".87"/>
<circle cx="391.8" cy="88.3" r="1.8"/>
<circle cx="395.6" cy="90.8" r="2"/>
<circle cx="398.1" cy="85.7" r="1.8"/>
<circle cx="400.7" cy="90.8" r=".87"/>
<circle cx="409.6" cy="90.8" r=".87"/>
<circle cx="410.8" cy="88.3" r="1.8"/>
<circle cx="414.7" cy="90.8" r="2"/>
<circle cx="417.2" cy="85.7" r="1.8"/>
<circle cx="419.7" cy="90.8" r=".87"/>
<circle cx="428.6" cy="90.8" r=".87"/>
<circle cx="429.9" cy="88.3" r="1.8"/>
<circle cx="433.7" cy="90.8" r="2"/>
<circle cx="436.2" cy="85.7" r="1.8"/>
<circle cx="438.8" cy="90.8" r=".87"/>
<circle cx="448.9" cy="97.8" r="1.8"/>
<circle cx="455.3" cy="95.3" r="1.8"/>
<circle cx="47.6" cy="109.9" r=".87"/>
<circle cx="48.9" cy="107.3" r="1.8"/>
<circle cx="52.7" cy="109.9" r="2"/>
<circle cx="55.2" cy="104.8" r="1.8"/>
<circle cx="57.8" cy="109.9" r=".87"/>
<circle cx="71.4" cy="109.9" r=".87"/>
<circle cx="72.7" cy="107.3" r="1.8"/>
<circle cx="76.5" cy="109.9" r="2"/>
<circle cx="79.1" cy="104.8" r="1.8"/>
<circle cx="81.6" cy="109.9" r=".87"/>
<circle cx="90.5" cy="109.9" r=".87"/>
<circle cx="91.8" cy="107.3" r="1.8"/>
<circle cx="95.6" cy="109.9" r="2"/>
<circle cx="98.1" cy="104.8" r="1.8"/>
<circle cx="100.6" cy="109.9" r=".87"/>
<circle cx="109.5" cy="109.9" r=".87"/>
<circle cx="110.8" cy="107.3" r="1.8"/>
<circle cx="114.6" cy="109.9" r="2"/>
<circle cx="117.2" cy="104.8" r="1.8"/>
<circle cx="119.7" cy="109.9" r=".87"/>
<circle cx="128.6" cy="109.9" r=".87"/>
<circle cx="129.9" cy="107.3" r="1.8"/>
<circle cx="133.7" cy="109.9" r="2"/>
<circle cx="136.2" cy="104.8" r="1.8"/>
<circle cx="138.7" cy="109.9" r=".87"/>
<circle cx="147.6" cy="109.9" r=".87"/>
<circle cx="148.9" cy="107.3" r="1.8"/>
<circle cx="152.7" cy="109.9" r="2"/>
<circle cx="155.3" cy="104.8" r="1.8"/>
<circle cx="157.8" cy="109.9" r=".87"/>
<circle cx="166.7" cy="109.9" r=".87"/>
<circle cx="168" cy="107.3" r="1.8"/>
<circle cx="171.8" cy="109.9" r="2"/>
<circle cx="174.3" cy="104.8" r="1.8"/>
<circle cx="176.8" cy="109.9" r=".87"/>
<circle cx="185.7" cy="109.9" r=".87"/>
<circle cx="187" cy="107.3" r="1.8"/>
<circle cx="190.8" cy="109.9" r="2"/>
<circle cx="193.4" cy="104.8" r="1.8"/>
<circle cx="195.9" cy="109.9" r=".87"/>
<circle cx="204.8" cy="109.9" r=".87"/>
<circle cx="206.1" cy="107.3" r="1.8"/>
<circle cx="209.9" cy="109.9" r="2"/>
<circle cx="212.4" cy="104.8" r="1.8"/>
<circle cx="214.9" cy="109.9" r=".87"/>
<circle cx="223.8" cy="109.9" r=".87"/>
<circle cx="225.1" cy="107.3" r="1.8"/>
<circle cx="228.9" cy="109.9" r="2"/>
<circle cx="231.5" cy="104.8" r="1.8"/>
<circle cx="234" cy="109.9" r=".87"/>
<circle cx="242.9" cy="109.9" r=".87"/>
<circle cx="244.2" cy="107.3" r="1.8"/>
<circle cx="248" cy="109.9" r="2"/>
<circle cx="250.5" cy="104.8" r="1.8"/>
<circle cx="253" cy="109.9" r=".87"/>
<circle cx="261.9" cy="109.9" r=".87"/>
<circle cx="263.2" cy="107.3" r="1.8"/>
<circle cx="267" cy="109.9" r="2"/>
<circle cx="269.6" cy="104.8" r="1.8"/>
<circle cx="272.1" cy="109.9" r=".87"/>
<circle cx="281" cy="110" r=".87"/>
<circle cx="282.3" cy="107.5" r="1.8"/>
<circle cx="286.1" cy="110" r="2"/>
<circle cx="288.6" cy="104.9" r="1.8"/>
<circle cx="291.1" cy="110" r=".87"/>
<circle cx="302.4" cy="100.3" r=".87"/>
<circle cx="307.5" cy="100.3" r="2"/>
<circle cx="312.6" cy="100.3" r=".87"/>
<circle cx="390.5" cy="109.9" r=".87"/>
<circle cx="391.8" cy="107.3" r="1.8"/>
<circle cx="395.6" cy="109.9" r="2"/>
<circle cx="398.1" cy="104.8" r="1.8"/>
<circle cx="400.7" cy="109.9" r=".87"/>
<circle cx="409.6" cy="109.9" r=".87"/>
<circle cx="410.8" cy="107.3" r="1.8"/>
<circle cx="414.7" cy="109.9" r="2"/>
<circle cx="417.2" cy="104.8" r="1.8"/>
<circle cx="419.7" cy="109.9" r=".87"/>
<circle cx="428.6" cy="109.9" r=".87"/>
<circle cx="429.9" cy="107.3" r="1.8"/>
<circle cx="433.7" cy="109.9" r="2"/>
<circle cx="436.2" cy="104.8" r="1.8"/>
<circle cx="438.8" cy="109.9" r=".87"/>
<circle cx="447.7" cy="100.3" r=".87"/>
<circle cx="452.8" cy="100.3" r="2"/>
<circle cx="457.8" cy="100.3" r=".87"/>
<circle cx="42.9" cy="128.9" r=".87"/>
<circle cx="44.1" cy="126.4" r="1.8"/>
<circle cx="47.9" cy="128.9" r="2"/>
<circle cx="50.5" cy="123.8" r="1.8"/>
<circle cx="53" cy="128.9" r=".87"/>
<circle cx="61.9" cy="128.9" r=".87"/>
<circle cx="63.2" cy="126.4" r="1.8"/>
<circle cx="67" cy="128.9" r="2"/>
<circle cx="69.5" cy="123.8" r="1.8"/>
<circle cx="72.1" cy="128.9" r=".87"/>
<circle cx="81" cy="128.9" r=".87"/>
<circle cx="82.2" cy="126.4" r="1.8"/>
<circle cx="86" cy="128.9" r="2"/>
<circle cx="88.6" cy="123.8" r="1.8"/>
<circle cx="91.1" cy="128.9" r=".87"/>
<circle cx="100" cy="128.9" r=".87"/>
<circle cx="101.3" cy="126.4" r="1.8"/>
<circle cx="105.1" cy="128.9" r="2"/>
<circle cx="107.6" cy="123.8" r="1.8"/>
<circle cx="110.2" cy="128.9" r=".87"/>
<circle cx="119.1" cy="128.9" r=".87"/>
<circle cx="120.3" cy="126.4" r="1.8"/>
<circle cx="124.1" cy="128.9" r="2"/>
<circle cx="126.7" cy="123.8" r="1.8"/>
<circle cx="129.2" cy="128.9" r=".87"/>
<circle cx="138.1" cy="128.9" r=".87"/>
<circle cx="139.4" cy="126.4" r="1.8"/>
<circle cx="143.2" cy="128.9" r="2"/>
<circle cx="145.7" cy="123.8" r="1.8"/>
<circle cx="148.3" cy="128.9" r=".87"/>
<circle cx="157.2" cy="128.9" r=".87"/>
<circle cx="158.4" cy="126.4" r="1.8"/>
<circle cx="162.2" cy="128.9" r="2"/>
<circle cx="164.8" cy="123.8" r="1.8"/>
<circle cx="167.3" cy="128.9" r=".87"/>
<circle cx="176.2" cy="128.9" r=".87"/>
<circle cx="177.5" cy="126.4" r="1.8"/>
<circle cx="181.3" cy="128.9" r="2"/>
<circle cx="183.8" cy="123.8" r="1.8"/>
<circle cx="186.4" cy="128.9" r=".87"/>
<circle cx="195.3" cy="128.9" r=".87"/>
<circle cx="196.5" cy="126.4" r="1.8"/>
<circle cx="200.3" cy="128.9" r="2"/>
<circle cx="202.9" cy="123.8" r="1.8"/>
<circle cx="205.4" cy="128.9" r=".87"/>
<circle cx="214.3" cy="128.9" r=".87"/>
<circle cx="215.6" cy="126.4" r="1.8"/>
<circle cx="219.4" cy="128.9" r="2"/>
<circle cx="221.9" cy="123.8" r="1.8"/>
<circle cx="224.5" cy="128.9" r=".87"/>
<circle cx="233.4" cy="128.9" r=".87"/>
<circle cx="234.6" cy="126.4" r="1.8"/>
<circle cx="238.4" cy="128.9" r="2"/>
<circle cx="241" cy="123.8" r="1.8"/>
<circle cx="243.5" cy="128.9" r=".87"/>
<circle cx="252.4" cy="128.9" r=".87"/>
<circle cx="253.7" cy="126.4" r="1.8"/>
<circle cx="257.5" cy="128.9" r="2"/>
<circle cx="260" cy="123.8" r="1.8"/>
<circle cx="262.6" cy="128.9" r=".87"/>
<circle cx="288.1" cy="128.9" r=".87"/>
<circle cx="289.4" cy="126.4" r="1.8"/>
<circle cx="293.2" cy="128.9" r="2"/>
<circle cx="295.8" cy="123.8" r="1.8"/>
<circle cx="298.3" cy="128.9" r=".87"/>
<circle cx="347.7" cy="128.9" r=".87"/>
<circle cx="348.9" cy="126.4" r="1.8"/>
<circle cx="352.7" cy="128.9" r="2"/>
<circle cx="355.3" cy="123.8" r="1.8"/>
<circle cx="357.8" cy="128.9" r=".87"/>
<circle cx="390.5" cy="128.9" r=".87"/>
<circle cx="391.8" cy="126.4" r="1.8"/>
<circle cx="395.6" cy="128.9" r="2"/>
<circle cx="398.1" cy="123.8" r="1.8"/>
<circle cx="400.7" cy="128.9" r=".87"/>
<circle cx="409.6" cy="128.9" r=".87"/>
<circle cx="410.8" cy="126.4" r="1.8"/>
<circle cx="414.7" cy="128.9" r="2"/>
<circle cx="417.2" cy="123.8" r="1.8"/>
<circle cx="419.7" cy="128.9" r=".87"/>
<circle cx="428.6" cy="128.9" r=".87"/>
<circle cx="429.9" cy="126.4" r="1.8"/>
<circle cx="433.7" cy="128.9" r="2"/>
<circle cx="436.2" cy="123.8" r="1.8"/>
<circle cx="438.8" cy="128.9" r=".87"/>
<circle cx="447.7" cy="138.4" r=".87"/>
<circle cx="448.9" cy="135.9" r="1.8"/>
<circle cx="452.8" cy="138.4" r="2"/>
<circle cx="455.3" cy="133.4" r="1.8"/>
<circle cx="457.8" cy="138.4" r=".87"/>
<circle cx="40.5" cy="148" r=".87"/>
<circle cx="41.8" cy="145.4" r="1.8"/>
<circle cx="45.6" cy="148" r="2"/>
<circle cx="48.1" cy="142.9" r="1.8"/>
<circle cx="50.6" cy="148" r=".87"/>
<circle cx="64.3" cy="148" r=".87"/>
<circle cx="65.6" cy="145.4" r="1.8"/>
<circle cx="69.4" cy="148" r="2"/>
<circle cx="71.9" cy="142.9" r="1.8"/>
<circle cx="74.5" cy="148" r=".87"/>
<circle cx="88.4" cy="148" r=".87"/>
<circle cx="89.7" cy="145.4" r="1.8"/>
<circle cx="93.5" cy="148" r="2"/>
<circle cx="96" cy="142.9" r="1.8"/>
<circle cx="98.6" cy="148" r=".87"/>
<circle cx="159.5" cy="148" r=".87"/>
<circle cx="160.8" cy="145.4" r="1.8"/>
<circle cx="164.6" cy="148" r="2"/>
<circle cx="167.2" cy="142.9" r="1.8"/>
<circle cx="169.7" cy="148" r=".87"/>
<circle cx="231" cy="148" r=".87"/>
<circle cx="232.3" cy="145.4" r="1.8"/>
<circle cx="236.1" cy="148" r="2"/>
<circle cx="238.6" cy="142.9" r="1.8"/>
<circle cx="241.1" cy="148" r=".87"/>
<circle cx="254.8" cy="148" r=".87"/>
<circle cx="256.1" cy="145.4" r="1.8"/>
<circle cx="259.9" cy="148" r="2"/>
<circle cx="262.4" cy="142.9" r="1.8"/>
<circle cx="265" cy="148" r=".87"/>
<circle cx="278.6" cy="148" r=".87"/>
<circle cx="279.9" cy="145.4" r="1.8"/>
<circle cx="283.7" cy="148" r="2"/>
<circle cx="286.2" cy="142.9" r="1.8"/>
<circle cx="288.8" cy="148" r=".87"/>
<circle cx="302.1" cy="148" r=".87"/>
<circle cx="303.4" cy="145.4" r="1.8"/>
<circle cx="307.2" cy="148" r="2"/>
<circle cx="309.7" cy="142.9" r="1.8"/>
<circle cx="312.3" cy="148" r=".87"/>
<circle cx="328.6" cy="148" r=".87"/>
<circle cx="329.9" cy="145.4" r="1.8"/>
<circle cx="333.7" cy="148" r="2"/>
<circle cx="336.2" cy="142.9" r="1.8"/>
<circle cx="338.8" cy="148" r=".87"/>
<circle cx="347.7" cy="148" r=".87"/>
<circle cx="348.9" cy="145.4" r="1.8"/>
<circle cx="352.7" cy="148" r="2"/>
<circle cx="355.3" cy="142.9" r="1.8"/>
<circle cx="357.8" cy="148" r=".87"/>
<circle cx="366.7" cy="148" r=".87"/>
<circle cx="368" cy="145.4" r="1.8"/>
<circle cx="371.8" cy="148" r="2"/>
<circle cx="374.3" cy="142.9" r="1.8"/>
<circle cx="376.9" cy="148" r=".87"/>
<circle cx="400.1" cy="148" r=".87"/>
<circle cx="401.3" cy="145.4" r="1.8"/>
<circle cx="405.1" cy="148" r="2"/>
<circle cx="407.7" cy="142.9" r="1.8"/>
<circle cx="410.2" cy="148" r=".87"/>
<circle cx="428.6" cy="148" r=".87"/>
<circle cx="429.9" cy="145.4" r="1.8"/>
<circle cx="433.7" cy="148" r="2"/>
<circle cx="436.2" cy="142.9" r="1.8"/>
<circle cx="438.8" cy="148" r=".87"/>
<circle cx="24.6" cy="166.5" r="1.6"/>
<circle cx="173.5" cy="166.5" r="1.6"/>
<circle cx="322.4" cy="166.5" r="1.6"/>
<circle cx="471.3" cy="166.5" r="1.6"/>
</g>
</svg>
